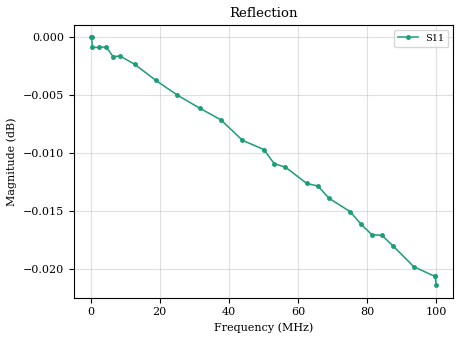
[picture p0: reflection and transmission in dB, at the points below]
! ListType=Lin
!!SAA-2 female short 0.1 to 100MHz 500 points
# MHz S RI R 50
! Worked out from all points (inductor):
!   500 points, 100 kHz to 100 MHz, reference 50 ohm
!   read as one part to ground: L = 2.64 nH near 500.4 kHz
!   highest Q = 29.6 at 8.508 MHz (marker M1), where L = 2.55 nH
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0.1  -1 7.71e-05
0.3002004  -1 0.000207
0.5004008  -0.9999 0.000336
2.502405  -0.9999 0.00163
4.504409  -0.9999 0.00291
6.506413  -0.9998 0.00418
8.508417  -0.9998 0.00544
12.71263  -0.9997 0.00808
18.91884  -0.9995 0.0119
25.12505  -0.9993 0.0158
31.53146  -0.9991 0.0198
37.73768  -0.9989 0.0236
43.94389  -0.9986 0.0274
50.1501  -0.9984 0.0311
53.15311  -0.9982 0.0329
56.35631  -0.9981 0.0349
62.56253  -0.9978 0.0386
65.76573  -0.9977 0.0405
68.96894  -0.9975 0.0424
75.17515  -0.9972 0.0461
78.17816  -0.997 0.0478
81.38136  -0.9968 0.0497
84.38437  -0.9967 0.0515
87.58758  -0.9965 0.0533
93.59359  -0.9961 0.0568
99.5996  -0.9958 0.0603
99.7998  -0.9958 0.0604
100  -0.9957 0.0605
